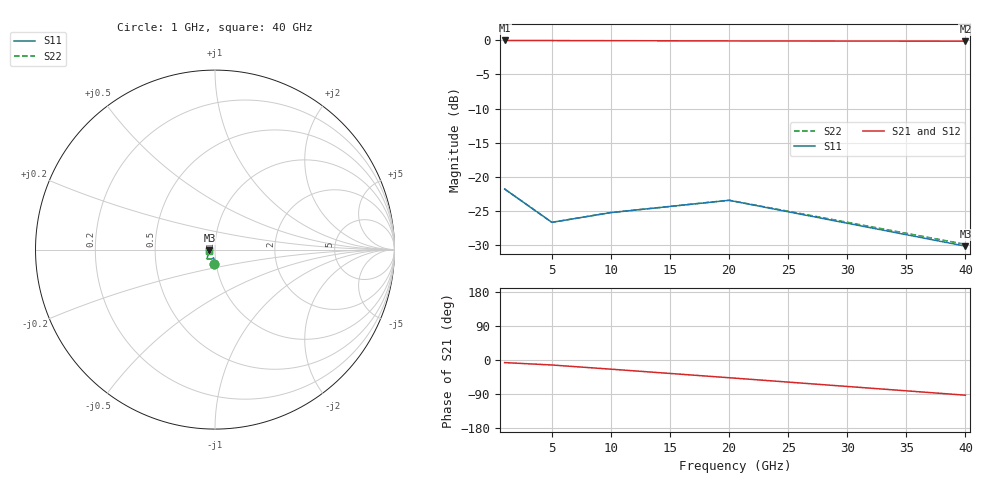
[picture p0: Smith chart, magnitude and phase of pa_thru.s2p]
! Generated by circuitRF - EM: Palace
! circuitRF-EM setup: g_thru_sheets
! circuitRF-EM layout: thru/layout/thru.clay
! circuitRF-EM written: 2026-11-04 23:24:58Z
! circuitRF-EM geometry: d10b097e4b397d61
! circuitRF-EM mesh: be36879526fbbc1a
! circuitRF-EM ports: 1a591d5b5a03db7b
! circuitRF-EM model: Palace 0.18.1 (0dc74cd, schema 1-7-0)
! Port[1] = port/1
! Port[2] = port/2
! circuitRF-EM port 1: 'port/1' from 'airbox/zmin' to 'Metal1/1', wave (mode 1), 50 Ohm: Palace's S is referred to the mode's own impedance Z_PV, renormalised here to 50 Ohm; reference plane 0 um into the structure from the port face
! circuitRF-EM port 2: 'port/2' from 'airbox/zmin' to 'Metal1/1', wave (mode 1), 50 Ohm: Palace's S is referred to the mode's own impedance Z_PV, renormalised here to 50 Ohm; reference plane 0 um into the structure from the port face
! circuitRF-EM 3D mesh: 14,778 elements initially, 14,778 finally, 0 adaptive pass(es), element order 2
! circuitRF-EM 3D operating temperature: 20 C
! circuitRF-EM 3D run: preset Standard; 14778 -> 14778 tetrahedra; 102310 unknowns; 0 refinement pass(es); 6 frequency sample(s)
! circuitRF-EM 3D run cost: wall 432 s; Palace peak memory 1.9 GB
! circuitRF-EM 3D DC row: circuitRF conduction solve of the conductors, 368 elements, 0.2 s; ports as terminal pairs
! circuitRF-EM: re-running the EM setup rewrites this file. If circuitRF reports it as stale, the layout's cross-section changed after this file was written.
# GHz S RI R 50
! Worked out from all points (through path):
!   5 points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, 1 GHz to 40 GHz, reference 50 ohm
!   highest |S21| = -0.02 dB at 1 GHz (marker M1); lowest = -0.1 dB at 40 GHz (marker M2)
!   lowest |S11| = -30.1 dB at 40 GHz (marker M3), VSWR 1.06, Z = 47 - j0.467 ohm
!   |S11| at or under -10 dB: start of sweep to end of sweep
!   |S22| runs from -29.9 to -21.8 dB; largest |S21 - S12| = 7.2e-06
1  -0.00535 -0.0814  0.991 -0.1189  0.991 -0.1189  -0.00534 -0.0814
5  -0.00773 -0.0459  0.9704 -0.2273  0.9704 -0.2273  -0.00768 -0.0459
10  -0.0187 -0.0515  0.907 -0.4077  0.907 -0.4077  -0.0185 -0.0516
20  -0.0447 -0.0505  0.6779 -0.7216  0.6779 -0.7216  -0.0441 -0.0511
40  -0.0307 -0.00496  -0.0494 -0.9847  -0.0494 -0.9847  -0.0309 -0.00859
